VERSION 5.8 ;
BUSBITCHARS "[]" ;
DIVIDERCHAR "/" ;
UNITS
    DATABASE MICRONS 1000 ;
END UNITS

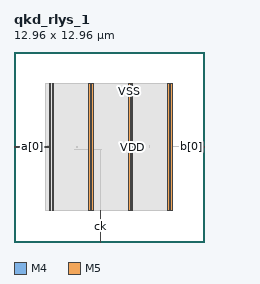
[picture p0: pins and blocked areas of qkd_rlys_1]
MACRO qkd_rlys_1
  FOREIGN qkd_rlys_1 0 0 ;
  CLASS BLOCK ;
  SIZE 12.96 BY 12.96 ;
  PIN a[0]
    DIRECTION INPUT ;
    USE SIGNAL ;
    PORT
      LAYER M4 ;
        RECT  0 6.48 0.084 6.504 ;
    END
    PORT
      LAYER M4 ;
        RECT  0.06 6.48 2.408 6.504 ;
    END
  END a[0]
  PIN b[0]
    DIRECTION OUTPUT ;
    USE SIGNAL ;
    PORT
      LAYER M4 ;
        RECT  12.876 6.48 12.96 6.504 ;
    END
    PORT
      LAYER M4 ;
        RECT  11.886 6.48 12.924 6.504 ;
    END
  END b[0]
  PIN ck
    DIRECTION INPUT ;
    USE SIGNAL ;
    PORT
      LAYER M5 ;
        RECT  5.904 0 5.928 0.084 ;
    END
    PORT
      LAYER M5 ;
        RECT  5.904 0.016 5.928 2.137 ;
    END
  END ck
  PIN VDD
    DIRECTION INOUT ;
    USE POWER ;
    PORT
      LAYER M5 ;
        RECT  10.692 2.151 10.812 10.809 ;
        RECT  7.992 2.151 8.112 10.809 ;
        RECT  5.292 2.151 5.412 10.809 ;
        RECT  2.592 2.151 2.712 10.809 ;
    END
  END VDD
  PIN VSS
    DIRECTION INOUT ;
    USE GROUND ;
    PORT
      LAYER M5 ;
        RECT  10.5 2.137 10.62 10.823 ;
        RECT  7.8 2.137 7.92 10.823 ;
        RECT  5.1 2.137 5.22 10.823 ;
        RECT  2.4 2.137 2.52 10.823 ;
    END
  END VSS
  # OT_OBS_CLOSED layer=M5 d_um=1.536 added=0
  OBS
    LAYER RVTN ;
     RECT  2.16 2.16 10.8 2.295 ;
     RECT  2.16 2.565 10.8 2.835 ;
     RECT  2.16 3.105 10.8 3.375 ;
     RECT  2.16 3.645 10.8 3.915 ;
     RECT  2.16 4.185 10.8 4.455 ;
     RECT  2.16 4.725 10.8 4.995 ;
     RECT  2.16 5.265 10.8 5.535 ;
     RECT  2.16 5.805 10.8 6.075 ;
     RECT  2.16 6.345 10.8 6.615 ;
     RECT  2.16 6.885 10.8 7.155 ;
     RECT  2.16 7.425 10.8 7.695 ;
     RECT  2.16 7.965 10.8 8.235 ;
     RECT  2.16 8.505 10.8 8.775 ;
     RECT  2.16 9.045 10.8 9.315 ;
     RECT  2.16 9.585 10.8 9.855 ;
     RECT  2.16 10.125 10.8 10.395 ;
     RECT  2.16 10.665 10.8 10.8 ;
    LAYER RVTP ;
     RECT  2.16 2.295 10.8 2.565 ;
     RECT  2.16 2.835 10.8 3.105 ;
     RECT  2.16 3.375 10.8 3.645 ;
     RECT  2.16 3.915 10.8 4.185 ;
     RECT  2.16 4.455 10.8 4.725 ;
     RECT  2.16 4.995 10.8 5.265 ;
     RECT  2.16 5.535 10.8 5.805 ;
     RECT  2.16 6.075 10.8 6.345 ;
     RECT  2.16 6.615 10.8 6.885 ;
     RECT  2.16 7.155 10.8 7.425 ;
     RECT  2.16 7.695 10.8 7.965 ;
     RECT  2.16 8.235 10.8 8.505 ;
     RECT  2.16 8.775 10.8 9.045 ;
     RECT  2.16 9.315 10.8 9.585 ;
     RECT  2.16 9.855 10.8 10.125 ;
     RECT  2.16 10.395 10.8 10.665 ;
    LAYER M1 ;
     RECT  2.16 2.151 10.8 10.809 ;
    LAYER M2 ;
     RECT  2.16 2.151 10.8 10.809 ;
     RECT  10.8 2.421 10.812 10.539 ;
     RECT  10.812 6.516 11.975 6.534 ;
    LAYER M3 ;
     RECT  2.415 2.143 2.505 2.413 ;
     RECT  5.115 2.143 5.205 2.413 ;
     RECT  7.815 2.143 7.905 2.413 ;
     RECT  10.515 2.143 10.605 2.413 ;
     RECT  7.815 2.413 8.097 6.241 ;
     RECT  4.14 6.277 4.158 6.317 ;
     RECT  5.115 2.413 5.397 6.421 ;
     RECT  2.415 2.413 2.697 6.475 ;
     RECT  4.284 6.421 4.302 6.539 ;
     RECT  5.115 6.421 5.454 6.539 ;
     RECT  7.308 6.241 8.154 6.539 ;
     RECT  11.952 6.475 11.97 6.539 ;
     RECT  2.304 6.475 2.697 6.575 ;
     RECT  7.308 6.539 8.097 6.575 ;
     RECT  9.252 6.421 9.27 6.575 ;
     RECT  2.415 6.575 2.697 10.547 ;
     RECT  5.115 6.539 5.397 10.547 ;
     RECT  7.815 6.575 8.097 10.547 ;
     RECT  10.515 2.413 10.797 10.547 ;
     RECT  2.415 10.547 2.505 10.817 ;
     RECT  5.115 10.547 5.205 10.817 ;
     RECT  7.815 10.547 7.905 10.817 ;
     RECT  10.515 10.547 10.605 10.817 ;
    LAYER M4 ;
     RECT  2.408 2.148 2.512 10.812 ;
     RECT  2.512 2.418 2.704 10.542 ;
     RECT  4.129 6.288 5.108 6.312 ;
     RECT  5.108 2.148 5.212 10.812 ;
     RECT  5.212 2.418 5.404 10.542 ;
     RECT  5.404 6.288 5.939 6.312 ;
     RECT  7.808 2.148 7.912 10.812 ;
     RECT  7.912 2.418 8.104 10.542 ;
     RECT  10.508 2.148 10.612 10.812 ;
     RECT  10.612 2.418 10.804 10.542 ;
    LAYER M5 ;
     RECT  2.4 2.137 2.52 2.151 ;
     RECT  7.8 2.137 7.92 2.151 ;
     RECT  10.5 2.137 10.62 2.151 ;
     RECT  5.1 2.137 5.928 6.323 ;
     RECT  2.4 2.151 2.712 10.809 ;
     RECT  5.1 6.323 5.412 10.809 ;
     RECT  7.8 2.151 8.112 10.809 ;
     RECT  10.5 2.151 10.812 10.809 ;
     RECT  2.4 10.809 2.52 10.823 ;
     RECT  5.1 10.809 5.22 10.823 ;
     RECT  7.8 10.809 7.92 10.823 ;
     RECT  10.5 10.809 10.62 10.823 ;
  END
END qkd_rlys_1
END LIBRARY
